VERSION 5.7 ;
  NOWIREEXTENSIONATPIN ON ;
  DIVIDERCHAR "/" ;
  BUSBITCHARS "[]" ;
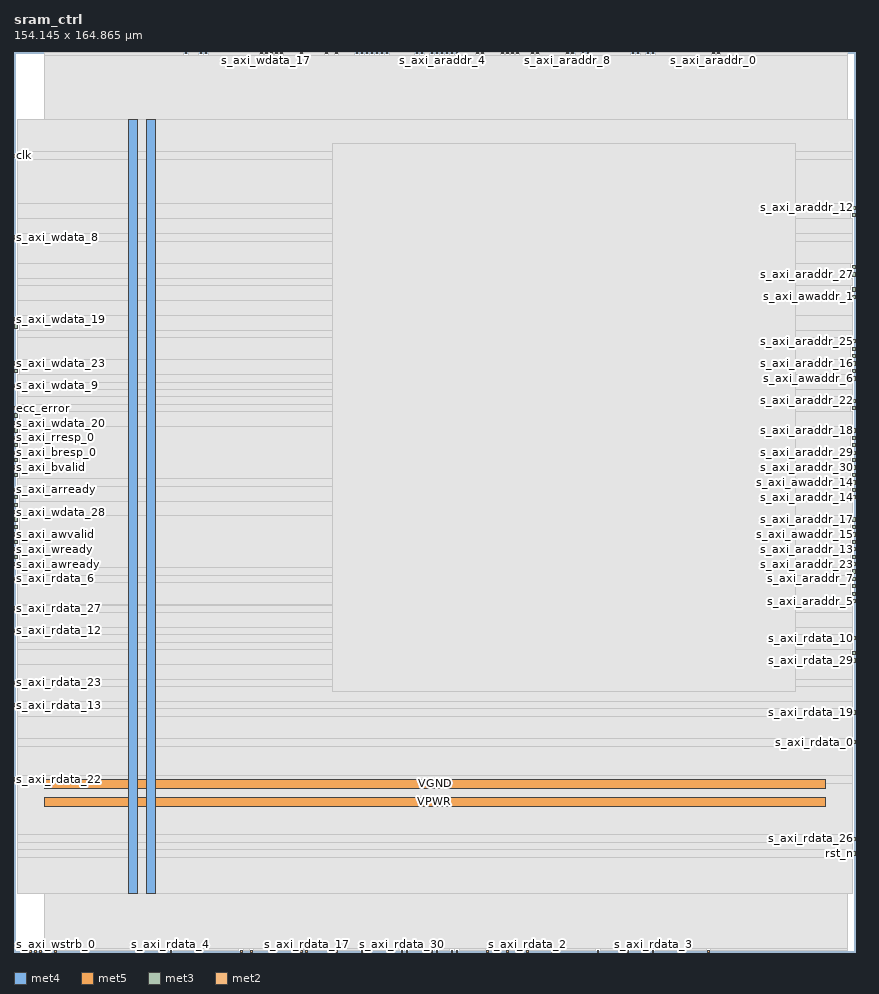
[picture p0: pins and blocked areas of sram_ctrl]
MACRO sram_ctrl
  CLASS BLOCK ;
  FOREIGN sram_ctrl ;
  ORIGIN 0.000 0.000 ;
  SIZE 154.145 BY 164.865 ;
  PIN VGND
    DIRECTION INOUT ;
    USE GROUND ;
    PORT
      LAYER met4 ;
        RECT 24.340 10.640 25.940 152.560 ;
    END
    PORT
      LAYER met5 ;
        RECT 5.520 30.030 148.580 31.630 ;
    END
  END VGND
  PIN VPWR
    DIRECTION INOUT ;
    USE POWER ;
    PORT
      LAYER met4 ;
        RECT 21.040 10.640 22.640 152.560 ;
    END
    PORT
      LAYER met5 ;
        RECT 5.520 26.730 148.580 28.330 ;
    END
  END VPWR
  PIN clk
    DIRECTION INPUT ;
    USE SIGNAL ;
    ANTENNAGATEAREA 1.286700 ;
    ANTENNADIFFAREA 0.434700 ;
    PORT
      LAYER met3 ;
        RECT 0.000 145.560 0.600 146.160 ;
    END
  END clk
  PIN ecc_error
    DIRECTION OUTPUT ;
    USE SIGNAL ;
    ANTENNAGATEAREA 0.434700 ;
    ANTENNADIFFAREA 0.775300 ;
    PORT
      LAYER met3 ;
        RECT 0.000 99.320 0.600 99.920 ;
    END
  END ecc_error
  PIN rst_n
    DIRECTION INPUT ;
    USE SIGNAL ;
    ANTENNAGATEAREA 0.647700 ;
    ANTENNADIFFAREA 0.434700 ;
    PORT
      LAYER met3 ;
        RECT 153.545 17.720 154.145 18.320 ;
    END
  END rst_n
  PIN s_axi_araddr_0
    DIRECTION INPUT ;
    USE SIGNAL ;
    ANTENNAGATEAREA 0.647700 ;
    ANTENNADIFFAREA 0.434700 ;
    PORT
      LAYER met2 ;
        RECT 127.970 164.585 128.250 164.865 ;
    END
  END s_axi_araddr_0
  PIN s_axi_araddr_1
    DIRECTION INPUT ;
    USE SIGNAL ;
    ANTENNAGATEAREA 0.647700 ;
    ANTENNADIFFAREA 0.434700 ;
    PORT
      LAYER met3 ;
        RECT 153.545 121.080 154.145 121.680 ;
    END
  END s_axi_araddr_1
  PIN s_axi_araddr_10
    DIRECTION INPUT ;
    USE SIGNAL ;
    ANTENNAGATEAREA 0.647700 ;
    ANTENNADIFFAREA 0.434700 ;
    PORT
      LAYER met2 ;
        RECT 79.210 164.585 79.490 164.865 ;
    END
  END s_axi_araddr_10
  PIN s_axi_araddr_11
    DIRECTION INPUT ;
    USE SIGNAL ;
    ANTENNAGATEAREA 0.647700 ;
    ANTENNADIFFAREA 0.434700 ;
    PORT
      LAYER met2 ;
        RECT 94.850 164.585 95.130 164.865 ;
    END
  END s_axi_araddr_11
  PIN s_axi_araddr_12
    DIRECTION INPUT ;
    USE SIGNAL ;
    ANTENNAGATEAREA 0.647700 ;
    ANTENNADIFFAREA 0.434700 ;
    PORT
      LAYER met3 ;
        RECT 153.545 136.040 154.145 136.640 ;
    END
  END s_axi_araddr_12
  PIN s_axi_araddr_13
    DIRECTION INPUT ;
    USE SIGNAL ;
    ANTENNAGATEAREA 0.647700 ;
    ANTENNADIFFAREA 0.434700 ;
    PORT
      LAYER met3 ;
        RECT 153.545 73.480 154.145 74.080 ;
    END
  END s_axi_araddr_13
  PIN s_axi_araddr_14
    DIRECTION INPUT ;
    USE SIGNAL ;
    ANTENNAGATEAREA 0.647700 ;
    ANTENNADIFFAREA 0.434700 ;
    PORT
      LAYER met3 ;
        RECT 153.545 83.000 154.145 83.600 ;
    END
  END s_axi_araddr_14
  PIN s_axi_araddr_15
    DIRECTION INPUT ;
    USE SIGNAL ;
    ANTENNAGATEAREA 0.647700 ;
    ANTENNADIFFAREA 0.434700 ;
    PORT
      LAYER met3 ;
        RECT 153.545 74.840 154.145 75.440 ;
    END
  END s_axi_araddr_15
  PIN s_axi_araddr_16
    DIRECTION INPUT ;
    USE SIGNAL ;
    ANTENNAGATEAREA 0.647700 ;
    ANTENNADIFFAREA 0.434700 ;
    PORT
      LAYER met3 ;
        RECT 153.545 107.480 154.145 108.080 ;
    END
  END s_axi_araddr_16
  PIN s_axi_araddr_17
    DIRECTION INPUT ;
    USE SIGNAL ;
    ANTENNAGATEAREA 0.647700 ;
    ANTENNADIFFAREA 0.434700 ;
    PORT
      LAYER met3 ;
        RECT 153.545 78.920 154.145 79.520 ;
    END
  END s_axi_araddr_17
  PIN s_axi_araddr_18
    DIRECTION INPUT ;
    USE SIGNAL ;
    ANTENNAGATEAREA 0.647700 ;
    ANTENNADIFFAREA 0.434700 ;
    PORT
      LAYER met3 ;
        RECT 153.545 95.240 154.145 95.840 ;
    END
  END s_axi_araddr_18
  PIN s_axi_araddr_19
    DIRECTION INPUT ;
    USE SIGNAL ;
    ANTENNAGATEAREA 0.647700 ;
    ANTENNADIFFAREA 0.434700 ;
    PORT
      LAYER met3 ;
        RECT 153.545 84.360 154.145 84.960 ;
    END
  END s_axi_araddr_19
  PIN s_axi_araddr_2
    DIRECTION INPUT ;
    USE SIGNAL ;
    ANTENNAGATEAREA 0.647700 ;
    ANTENNADIFFAREA 0.434700 ;
    PORT
      LAYER met2 ;
        RECT 80.130 0.000 80.410 0.280 ;
    END
  END s_axi_araddr_2
  PIN s_axi_araddr_20
    DIRECTION INPUT ;
    USE SIGNAL ;
    ANTENNAGATEAREA 0.647700 ;
    ANTENNADIFFAREA 0.434700 ;
    PORT
      LAYER met2 ;
        RECT 76.450 164.585 76.730 164.865 ;
    END
  END s_axi_araddr_20
  PIN s_axi_araddr_21
    DIRECTION INPUT ;
    USE SIGNAL ;
    ANTENNAGATEAREA 0.647700 ;
    ANTENNADIFFAREA 0.434700 ;
    PORT
      LAYER met2 ;
        RECT 113.250 164.585 113.530 164.865 ;
    END
  END s_axi_araddr_21
  PIN s_axi_araddr_22
    DIRECTION INPUT ;
    USE SIGNAL ;
    ANTENNAGATEAREA 0.647700 ;
    ANTENNADIFFAREA 0.434700 ;
    PORT
      LAYER met3 ;
        RECT 153.545 100.680 154.145 101.280 ;
    END
  END s_axi_araddr_22
  PIN s_axi_araddr_23
    DIRECTION INPUT ;
    USE SIGNAL ;
    ANTENNAGATEAREA 0.647700 ;
    ANTENNADIFFAREA 0.434700 ;
    PORT
      LAYER met3 ;
        RECT 153.545 70.760 154.145 71.360 ;
    END
  END s_axi_araddr_23
  PIN s_axi_araddr_24
    DIRECTION INPUT ;
    USE SIGNAL ;
    ANTENNAGATEAREA 0.647700 ;
    ANTENNADIFFAREA 0.434700 ;
    PORT
      LAYER met2 ;
        RECT 104.050 164.585 104.330 164.865 ;
    END
  END s_axi_araddr_24
  PIN s_axi_araddr_25
    DIRECTION INPUT ;
    USE SIGNAL ;
    ANTENNAGATEAREA 0.647700 ;
    ANTENNADIFFAREA 0.434700 ;
    PORT
      LAYER met3 ;
        RECT 153.545 111.560 154.145 112.160 ;
    END
  END s_axi_araddr_25
  PIN s_axi_araddr_26
    DIRECTION INPUT ;
    USE SIGNAL ;
    ANTENNAGATEAREA 0.647700 ;
    ANTENNADIFFAREA 0.434700 ;
    PORT
      LAYER met2 ;
        RECT 89.330 164.585 89.610 164.865 ;
    END
  END s_axi_araddr_26
  PIN s_axi_araddr_27
    DIRECTION INPUT ;
    USE SIGNAL ;
    ANTENNAGATEAREA 0.647700 ;
    ANTENNADIFFAREA 0.434700 ;
    PORT
      LAYER met3 ;
        RECT 153.545 123.800 154.145 124.400 ;
    END
  END s_axi_araddr_27
  PIN s_axi_araddr_28
    DIRECTION INPUT ;
    USE SIGNAL ;
    ANTENNAGATEAREA 0.647700 ;
    ANTENNADIFFAREA 0.434700 ;
    PORT
      LAYER met2 ;
        RECT 84.730 164.585 85.010 164.865 ;
    END
  END s_axi_araddr_28
  PIN s_axi_araddr_29
    DIRECTION INPUT ;
    USE SIGNAL ;
    ANTENNAGATEAREA 0.647700 ;
    ANTENNADIFFAREA 0.434700 ;
    PORT
      LAYER met3 ;
        RECT 153.545 91.160 154.145 91.760 ;
    END
  END s_axi_araddr_29
  PIN s_axi_araddr_3
    DIRECTION INPUT ;
    USE SIGNAL ;
    ANTENNAGATEAREA 0.647700 ;
    ANTENNADIFFAREA 0.434700 ;
    PORT
      LAYER met2 ;
        RECT 116.010 164.585 116.290 164.865 ;
    END
  END s_axi_araddr_3
  PIN s_axi_araddr_30
    DIRECTION INPUT ;
    USE SIGNAL ;
    ANTENNAGATEAREA 0.647700 ;
    ANTENNADIFFAREA 0.434700 ;
    PORT
      LAYER met3 ;
        RECT 153.545 88.440 154.145 89.040 ;
    END
  END s_axi_araddr_30
  PIN s_axi_araddr_31
    DIRECTION INPUT ;
    USE SIGNAL ;
    ANTENNAGATEAREA 0.647700 ;
    ANTENNADIFFAREA 0.434700 ;
    PORT
      LAYER met2 ;
        RECT 74.610 164.585 74.890 164.865 ;
    END
  END s_axi_araddr_31
  PIN s_axi_araddr_4
    DIRECTION INPUT ;
    USE SIGNAL ;
    ANTENNAGATEAREA 0.647700 ;
    ANTENNADIFFAREA 0.434700 ;
    PORT
      LAYER met2 ;
        RECT 78.290 164.585 78.570 164.865 ;
    END
  END s_axi_araddr_4
  PIN s_axi_araddr_5
    DIRECTION INPUT ;
    USE SIGNAL ;
    ANTENNAGATEAREA 0.647700 ;
    ANTENNADIFFAREA 0.434700 ;
    PORT
      LAYER met3 ;
        RECT 153.545 63.960 154.145 64.560 ;
    END
  END s_axi_araddr_5
  PIN s_axi_araddr_6
    DIRECTION INPUT ;
    USE SIGNAL ;
    ANTENNAGATEAREA 0.647700 ;
    ANTENNADIFFAREA 0.434700 ;
    PORT
      LAYER met3 ;
        RECT 153.545 106.120 154.145 106.720 ;
    END
  END s_axi_araddr_6
  PIN s_axi_araddr_7
    DIRECTION INPUT ;
    USE SIGNAL ;
    ANTENNAGATEAREA 0.647700 ;
    ANTENNADIFFAREA 0.434700 ;
    PORT
      LAYER met3 ;
        RECT 153.545 68.040 154.145 68.640 ;
    END
  END s_axi_araddr_7
  PIN s_axi_araddr_8
    DIRECTION INPUT ;
    USE SIGNAL ;
    ANTENNAGATEAREA 0.647700 ;
    ANTENNADIFFAREA 0.434700 ;
    PORT
      LAYER met2 ;
        RECT 101.290 164.585 101.570 164.865 ;
    END
  END s_axi_araddr_8
  PIN s_axi_araddr_9
    DIRECTION INPUT ;
    USE SIGNAL ;
    ANTENNAGATEAREA 0.647700 ;
    ANTENNADIFFAREA 0.434700 ;
    PORT
      LAYER met2 ;
        RECT 90.250 164.585 90.530 164.865 ;
    END
  END s_axi_araddr_9
  PIN s_axi_arready
    DIRECTION OUTPUT ;
    USE SIGNAL ;
    ANTENNAGATEAREA 0.434700 ;
    ANTENNADIFFAREA 1.137600 ;
    PORT
      LAYER met3 ;
        RECT 0.000 84.360 0.600 84.960 ;
    END
  END s_axi_arready
  PIN s_axi_arvalid
    DIRECTION INPUT ;
    USE SIGNAL ;
    ANTENNAGATEAREA 0.647700 ;
    ANTENNADIFFAREA 0.434700 ;
    PORT
      LAYER met3 ;
        RECT 0.000 83.000 0.600 83.600 ;
    END
  END s_axi_arvalid
  PIN s_axi_awaddr_0
    DIRECTION INPUT ;
    USE SIGNAL ;
    ANTENNAGATEAREA 0.647700 ;
    ANTENNADIFFAREA 0.434700 ;
    PORT
      LAYER met2 ;
        RECT 128.890 164.585 129.170 164.865 ;
    END
  END s_axi_awaddr_0
  PIN s_axi_awaddr_1
    DIRECTION INPUT ;
    USE SIGNAL ;
    ANTENNAGATEAREA 0.647700 ;
    ANTENNADIFFAREA 0.434700 ;
    PORT
      LAYER met3 ;
        RECT 153.545 119.720 154.145 120.320 ;
    END
  END s_axi_awaddr_1
  PIN s_axi_awaddr_10
    DIRECTION INPUT ;
    USE SIGNAL ;
    ANTENNAGATEAREA 0.647700 ;
    ANTENNADIFFAREA 0.434700 ;
    PORT
      LAYER met2 ;
        RECT 81.050 164.585 81.330 164.865 ;
    END
  END s_axi_awaddr_10
  PIN s_axi_awaddr_11
    DIRECTION INPUT ;
    USE SIGNAL ;
    ANTENNAGATEAREA 0.647700 ;
    ANTENNADIFFAREA 0.434700 ;
    PORT
      LAYER met2 ;
        RECT 95.770 164.585 96.050 164.865 ;
    END
  END s_axi_awaddr_11
  PIN s_axi_awaddr_12
    DIRECTION INPUT ;
    USE SIGNAL ;
    ANTENNAGATEAREA 0.647700 ;
    ANTENNADIFFAREA 0.434700 ;
    PORT
      LAYER met3 ;
        RECT 153.545 134.680 154.145 135.280 ;
    END
  END s_axi_awaddr_12
  PIN s_axi_awaddr_13
    DIRECTION INPUT ;
    USE SIGNAL ;
    ANTENNAGATEAREA 0.647700 ;
    ANTENNADIFFAREA 0.434700 ;
    PORT
      LAYER met3 ;
        RECT 153.545 72.120 154.145 72.720 ;
    END
  END s_axi_awaddr_13
  PIN s_axi_awaddr_14
    DIRECTION INPUT ;
    USE SIGNAL ;
    ANTENNAGATEAREA 0.647700 ;
    ANTENNADIFFAREA 0.434700 ;
    PORT
      LAYER met3 ;
        RECT 153.545 85.720 154.145 86.320 ;
    END
  END s_axi_awaddr_14
  PIN s_axi_awaddr_15
    DIRECTION INPUT ;
    USE SIGNAL ;
    ANTENNAGATEAREA 0.647700 ;
    ANTENNADIFFAREA 0.434700 ;
    PORT
      LAYER met3 ;
        RECT 153.545 76.200 154.145 76.800 ;
    END
  END s_axi_awaddr_15
  PIN s_axi_awaddr_16
    DIRECTION INPUT ;
    USE SIGNAL ;
    ANTENNAGATEAREA 0.647700 ;
    ANTENNADIFFAREA 0.434700 ;
    PORT
      LAYER met3 ;
        RECT 153.545 108.840 154.145 109.440 ;
    END
  END s_axi_awaddr_16
  PIN s_axi_awaddr_17
    DIRECTION INPUT ;
    USE SIGNAL ;
    ANTENNAGATEAREA 0.647700 ;
    ANTENNADIFFAREA 0.434700 ;
    PORT
      LAYER met3 ;
        RECT 153.545 77.560 154.145 78.160 ;
    END
  END s_axi_awaddr_17
  PIN s_axi_awaddr_18
    DIRECTION INPUT ;
    USE SIGNAL ;
    ANTENNAGATEAREA 0.647700 ;
    ANTENNADIFFAREA 0.434700 ;
    PORT
      LAYER met3 ;
        RECT 153.545 93.880 154.145 94.480 ;
    END
  END s_axi_awaddr_18
  PIN s_axi_awaddr_19
    DIRECTION INPUT ;
    USE SIGNAL ;
    ANTENNAGATEAREA 0.647700 ;
    ANTENNADIFFAREA 0.434700 ;
    PORT
      LAYER met3 ;
        RECT 153.545 87.080 154.145 87.680 ;
    END
  END s_axi_awaddr_19
  PIN s_axi_awaddr_2
    DIRECTION INPUT ;
    USE SIGNAL ;
    ANTENNAGATEAREA 0.647700 ;
    ANTENNADIFFAREA 0.434700 ;
    PORT
      LAYER met2 ;
        RECT 81.050 0.000 81.330 0.280 ;
    END
  END s_axi_awaddr_2
  PIN s_axi_awaddr_20
    DIRECTION INPUT ;
    USE SIGNAL ;
    ANTENNAGATEAREA 0.647700 ;
    ANTENNADIFFAREA 0.434700 ;
    PORT
      LAYER met2 ;
        RECT 77.370 164.585 77.650 164.865 ;
    END
  END s_axi_awaddr_20
  PIN s_axi_awaddr_21
    DIRECTION INPUT ;
    USE SIGNAL ;
    ANTENNAGATEAREA 0.647700 ;
    ANTENNADIFFAREA 0.434700 ;
    PORT
      LAYER met2 ;
        RECT 114.170 164.585 114.450 164.865 ;
    END
  END s_axi_awaddr_21
  PIN s_axi_awaddr_22
    DIRECTION INPUT ;
    USE SIGNAL ;
    ANTENNAGATEAREA 0.647700 ;
    ANTENNADIFFAREA 0.434700 ;
    PORT
      LAYER met3 ;
        RECT 153.545 99.320 154.145 99.920 ;
    END
  END s_axi_awaddr_22
  PIN s_axi_awaddr_23
    DIRECTION INPUT ;
    USE SIGNAL ;
    ANTENNAGATEAREA 0.647700 ;
    ANTENNADIFFAREA 0.434700 ;
    PORT
      LAYER met3 ;
        RECT 153.545 69.400 154.145 70.000 ;
    END
  END s_axi_awaddr_23
  PIN s_axi_awaddr_24
    DIRECTION INPUT ;
    USE SIGNAL ;
    ANTENNAGATEAREA 0.647700 ;
    ANTENNADIFFAREA 0.434700 ;
    PORT
      LAYER met2 ;
        RECT 104.970 164.585 105.250 164.865 ;
    END
  END s_axi_awaddr_24
  PIN s_axi_awaddr_25
    DIRECTION INPUT ;
    USE SIGNAL ;
    ANTENNAGATEAREA 0.647700 ;
    ANTENNADIFFAREA 0.434700 ;
    PORT
      LAYER met3 ;
        RECT 153.545 110.200 154.145 110.800 ;
    END
  END s_axi_awaddr_25
  PIN s_axi_awaddr_26
    DIRECTION INPUT ;
    USE SIGNAL ;
    ANTENNAGATEAREA 0.647700 ;
    ANTENNADIFFAREA 0.434700 ;
    PORT
      LAYER met2 ;
        RECT 91.170 164.585 91.450 164.865 ;
    END
  END s_axi_awaddr_26
  PIN s_axi_awaddr_27
    DIRECTION INPUT ;
    USE SIGNAL ;
    ANTENNAGATEAREA 0.647700 ;
    ANTENNADIFFAREA 0.434700 ;
    PORT
      LAYER met3 ;
        RECT 153.545 125.160 154.145 125.760 ;
    END
  END s_axi_awaddr_27
  PIN s_axi_awaddr_28
    DIRECTION INPUT ;
    USE SIGNAL ;
    ANTENNAGATEAREA 0.647700 ;
    ANTENNADIFFAREA 0.434700 ;
    PORT
      LAYER met2 ;
        RECT 85.650 164.585 85.930 164.865 ;
    END
  END s_axi_awaddr_28
  PIN s_axi_awaddr_29
    DIRECTION INPUT ;
    USE SIGNAL ;
    ANTENNAGATEAREA 0.647700 ;
    ANTENNADIFFAREA 0.434700 ;
    PORT
      LAYER met3 ;
        RECT 153.545 89.800 154.145 90.400 ;
    END
  END s_axi_awaddr_29
  PIN s_axi_awaddr_3
    DIRECTION INPUT ;
    USE SIGNAL ;
    ANTENNAGATEAREA 0.647700 ;
    ANTENNADIFFAREA 0.434700 ;
    PORT
      LAYER met2 ;
        RECT 116.930 164.585 117.210 164.865 ;
    END
  END s_axi_awaddr_3
  PIN s_axi_awaddr_30
    DIRECTION INPUT ;
    USE SIGNAL ;
    ANTENNAGATEAREA 0.647700 ;
    ANTENNADIFFAREA 0.434700 ;
    PORT
      LAYER met3 ;
        RECT 153.545 92.520 154.145 93.120 ;
    END
  END s_axi_awaddr_30
  PIN s_axi_awaddr_31
    DIRECTION INPUT ;
    USE SIGNAL ;
    ANTENNAGATEAREA 0.647700 ;
    ANTENNADIFFAREA 0.434700 ;
    PORT
      LAYER met2 ;
        RECT 73.690 164.585 73.970 164.865 ;
    END
  END s_axi_awaddr_31
  PIN s_axi_awaddr_4
    DIRECTION INPUT ;
    USE SIGNAL ;
    ANTENNAGATEAREA 0.647700 ;
    ANTENNADIFFAREA 0.434700 ;
    PORT
      LAYER met2 ;
        RECT 80.130 164.585 80.410 164.865 ;
    END
  END s_axi_awaddr_4
  PIN s_axi_awaddr_5
    DIRECTION INPUT ;
    USE SIGNAL ;
    ANTENNAGATEAREA 0.647700 ;
    ANTENNADIFFAREA 0.434700 ;
    PORT
      LAYER met3 ;
        RECT 153.545 66.680 154.145 67.280 ;
    END
  END s_axi_awaddr_5
  PIN s_axi_awaddr_6
    DIRECTION INPUT ;
    USE SIGNAL ;
    ANTENNAGATEAREA 0.647700 ;
    ANTENNADIFFAREA 0.434700 ;
    PORT
      LAYER met3 ;
        RECT 153.545 104.760 154.145 105.360 ;
    END
  END s_axi_awaddr_6
  PIN s_axi_awaddr_7
    DIRECTION INPUT ;
    USE SIGNAL ;
    ANTENNAGATEAREA 0.647700 ;
    ANTENNADIFFAREA 0.434700 ;
    PORT
      LAYER met3 ;
        RECT 153.545 65.320 154.145 65.920 ;
    END
  END s_axi_awaddr_7
  PIN s_axi_awaddr_8
    DIRECTION INPUT ;
    USE SIGNAL ;
    ANTENNAGATEAREA 0.647700 ;
    ANTENNADIFFAREA 0.434700 ;
    PORT
      LAYER met2 ;
        RECT 102.210 164.585 102.490 164.865 ;
    END
  END s_axi_awaddr_8
  PIN s_axi_awaddr_9
    DIRECTION INPUT ;
    USE SIGNAL ;
    ANTENNAGATEAREA 0.647700 ;
    ANTENNADIFFAREA 0.434700 ;
    PORT
      LAYER met2 ;
        RECT 92.090 164.585 92.370 164.865 ;
    END
  END s_axi_awaddr_9
  PIN s_axi_awready
    DIRECTION OUTPUT ;
    USE SIGNAL ;
    ANTENNAGATEAREA 0.434700 ;
    ANTENNADIFFAREA 1.137600 ;
    PORT
      LAYER met3 ;
        RECT 0.000 70.760 0.600 71.360 ;
    END
  END s_axi_awready
  PIN s_axi_awvalid
    DIRECTION INPUT ;
    USE SIGNAL ;
    ANTENNAGATEAREA 0.647700 ;
    ANTENNADIFFAREA 0.434700 ;
    PORT
      LAYER met3 ;
        RECT 0.000 76.200 0.600 76.800 ;
    END
  END s_axi_awvalid
  PIN s_axi_bready
    DIRECTION INPUT ;
    USE SIGNAL ;
    PORT
      LAYER met2 ;
        RECT 1.930 0.000 2.210 0.280 ;
    END
  END s_axi_bready
  PIN s_axi_bresp_0
    DIRECTION OUTPUT ;
    USE SIGNAL ;
    ANTENNAGATEAREA 0.434700 ;
    ANTENNADIFFAREA 0.434700 ;
    PORT
      LAYER met3 ;
        RECT 0.000 91.160 0.600 91.760 ;
    END
  END s_axi_bresp_0
  PIN s_axi_bresp_1
    DIRECTION OUTPUT ;
    USE SIGNAL ;
    ANTENNAGATEAREA 0.434700 ;
    ANTENNADIFFAREA 0.775300 ;
    PORT
      LAYER met3 ;
        RECT 0.000 92.520 0.600 93.120 ;
    END
  END s_axi_bresp_1
  PIN s_axi_bvalid
    DIRECTION OUTPUT ;
    USE SIGNAL ;
    ANTENNAGATEAREA 0.434700 ;
    ANTENNADIFFAREA 1.137600 ;
    PORT
      LAYER met3 ;
        RECT 0.000 88.440 0.600 89.040 ;
    END
  END s_axi_bvalid
  PIN s_axi_rdata_0
    DIRECTION OUTPUT ;
    USE SIGNAL ;
    ANTENNAGATEAREA 0.434700 ;
    ANTENNADIFFAREA 1.137600 ;
    PORT
      LAYER met3 ;
        RECT 153.545 38.120 154.145 38.720 ;
    END
  END s_axi_rdata_0
  PIN s_axi_rdata_1
    DIRECTION OUTPUT ;
    USE SIGNAL ;
    ANTENNAGATEAREA 0.434700 ;
    ANTENNADIFFAREA 1.137600 ;
    PORT
      LAYER met2 ;
        RECT 112.330 0.000 112.610 0.280 ;
    END
  END s_axi_rdata_1
  PIN s_axi_rdata_10
    DIRECTION OUTPUT ;
    USE SIGNAL ;
    ANTENNAGATEAREA 0.434700 ;
    ANTENNADIFFAREA 1.137600 ;
    PORT
      LAYER met3 ;
        RECT 153.545 57.160 154.145 57.760 ;
    END
  END s_axi_rdata_10
  PIN s_axi_rdata_11
    DIRECTION OUTPUT ;
    USE SIGNAL ;
    ANTENNAGATEAREA 0.434700 ;
    ANTENNADIFFAREA 1.137600 ;
    PORT
      LAYER met2 ;
        RECT 98.530 0.000 98.810 0.280 ;
    END
  END s_axi_rdata_11
  PIN s_axi_rdata_12
    DIRECTION OUTPUT ;
    USE SIGNAL ;
    ANTENNAGATEAREA 0.434700 ;
    ANTENNADIFFAREA 1.137600 ;
    PORT
      LAYER met3 ;
        RECT 0.000 58.520 0.600 59.120 ;
    END
  END s_axi_rdata_12
  PIN s_axi_rdata_13
    DIRECTION OUTPUT ;
    USE SIGNAL ;
    ANTENNAGATEAREA 0.434700 ;
    ANTENNADIFFAREA 1.137600 ;
    PORT
      LAYER met3 ;
        RECT 0.000 44.920 0.600 45.520 ;
    END
  END s_axi_rdata_13
  PIN s_axi_rdata_14
    DIRECTION OUTPUT ;
    USE SIGNAL ;
    ANTENNAGATEAREA 0.434700 ;
    ANTENNADIFFAREA 1.137600 ;
    PORT
      LAYER met2 ;
        RECT 106.810 0.000 107.090 0.280 ;
    END
  END s_axi_rdata_14
  PIN s_axi_rdata_15
    DIRECTION OUTPUT ;
    USE SIGNAL ;
    ANTENNAGATEAREA 0.434700 ;
    ANTENNADIFFAREA 1.137600 ;
    PORT
      LAYER met2 ;
        RECT 76.450 0.000 76.730 0.280 ;
    END
  END s_axi_rdata_15
  PIN s_axi_rdata_16
    DIRECTION OUTPUT ;
    USE SIGNAL ;
    ANTENNAGATEAREA 0.434700 ;
    ANTENNADIFFAREA 1.137600 ;
    PORT
      LAYER met2 ;
        RECT 127.050 0.000 127.330 0.280 ;
    END
  END s_axi_rdata_16
  PIN s_axi_rdata_17
    DIRECTION OUTPUT ;
    USE SIGNAL ;
    ANTENNAGATEAREA 0.434700 ;
    ANTENNADIFFAREA 1.137600 ;
    PORT
      LAYER met2 ;
        RECT 53.450 0.000 53.730 0.280 ;
    END
  END s_axi_rdata_17
  PIN s_axi_rdata_18
    DIRECTION OUTPUT ;
    USE SIGNAL ;
    ANTENNAGATEAREA 0.434700 ;
    ANTENNADIFFAREA 1.137600 ;
    PORT
      LAYER met2 ;
        RECT 43.330 0.000 43.610 0.280 ;
    END
  END s_axi_rdata_18
  PIN s_axi_rdata_19
    DIRECTION OUTPUT ;
    USE SIGNAL ;
    ANTENNAGATEAREA 0.434700 ;
    ANTENNADIFFAREA 1.137600 ;
    PORT
      LAYER met3 ;
        RECT 153.545 43.560 154.145 44.160 ;
    END
  END s_axi_rdata_19
  PIN s_axi_rdata_2
    DIRECTION OUTPUT ;
    USE SIGNAL ;
    ANTENNAGATEAREA 0.434700 ;
    ANTENNADIFFAREA 1.137600 ;
    PORT
      LAYER met2 ;
        RECT 93.930 0.000 94.210 0.280 ;
    END
  END s_axi_rdata_2
  PIN s_axi_rdata_20
    DIRECTION OUTPUT ;
    USE SIGNAL ;
    ANTENNAGATEAREA 0.434700 ;
    ANTENNADIFFAREA 1.137600 ;
    PORT
      LAYER met3 ;
        RECT 0.000 72.120 0.600 72.720 ;
    END
  END s_axi_rdata_20
  PIN s_axi_rdata_21
    DIRECTION OUTPUT ;
    USE SIGNAL ;
    ANTENNAGATEAREA 0.434700 ;
    ANTENNADIFFAREA 1.137600 ;
    PORT
      LAYER met2 ;
        RECT 86.570 0.000 86.850 0.280 ;
    END
  END s_axi_rdata_21
  PIN s_axi_rdata_22
    DIRECTION OUTPUT ;
    USE SIGNAL ;
    ANTENNAGATEAREA 0.434700 ;
    ANTENNADIFFAREA 1.137600 ;
    PORT
      LAYER met3 ;
        RECT 0.000 31.320 0.600 31.920 ;
    END
  END s_axi_rdata_22
  PIN s_axi_rdata_23
    DIRECTION OUTPUT ;
    USE SIGNAL ;
    ANTENNAGATEAREA 0.434700 ;
    ANTENNADIFFAREA 1.137600 ;
    PORT
      LAYER met3 ;
        RECT 0.000 49.000 0.600 49.600 ;
    END
  END s_axi_rdata_23
  PIN s_axi_rdata_24
    DIRECTION OUTPUT ;
    USE SIGNAL ;
    ANTENNAGATEAREA 0.434700 ;
    ANTENNADIFFAREA 1.137600 ;
    PORT
      LAYER met2 ;
        RECT 63.570 0.000 63.850 0.280 ;
    END
  END s_axi_rdata_24
  PIN s_axi_rdata_25
    DIRECTION OUTPUT ;
    USE SIGNAL ;
    ANTENNAGATEAREA 0.434700 ;
    ANTENNADIFFAREA 1.137600 ;
    PORT
      LAYER met2 ;
        RECT 77.370 0.000 77.650 0.280 ;
    END
  END s_axi_rdata_25
  PIN s_axi_rdata_26
    DIRECTION OUTPUT ;
    USE SIGNAL ;
    ANTENNAGATEAREA 0.434700 ;
    ANTENNADIFFAREA 1.137600 ;
    PORT
      LAYER met3 ;
        RECT 153.545 20.440 154.145 21.040 ;
    END
  END s_axi_rdata_26
  PIN s_axi_rdata_27
    DIRECTION OUTPUT ;
    USE SIGNAL ;
    ANTENNAGATEAREA 0.434700 ;
    ANTENNADIFFAREA 1.137600 ;
    PORT
      LAYER met3 ;
        RECT 0.000 62.600 0.600 63.200 ;
    END
  END s_axi_rdata_27
  PIN s_axi_rdata_28
    DIRECTION OUTPUT ;
    USE SIGNAL ;
    ANTENNAGATEAREA 0.434700 ;
    ANTENNADIFFAREA 1.137600 ;
    PORT
      LAYER met2 ;
        RECT 41.490 0.000 41.770 0.280 ;
    END
  END s_axi_rdata_28
  PIN s_axi_rdata_29
    DIRECTION OUTPUT ;
    USE SIGNAL ;
    ANTENNAGATEAREA 0.434700 ;
    ANTENNADIFFAREA 1.137600 ;
    PORT
      LAYER met3 ;
        RECT 153.545 53.080 154.145 53.680 ;
    END
  END s_axi_rdata_29
  PIN s_axi_rdata_3
    DIRECTION OUTPUT ;
    USE SIGNAL ;
    ANTENNAGATEAREA 0.434700 ;
    ANTENNADIFFAREA 1.137600 ;
    PORT
      LAYER met2 ;
        RECT 116.930 0.000 117.210 0.280 ;
    END
  END s_axi_rdata_3
  PIN s_axi_rdata_30
    DIRECTION OUTPUT ;
    USE SIGNAL ;
    ANTENNAGATEAREA 0.434700 ;
    ANTENNADIFFAREA 1.137600 ;
    PORT
      LAYER met2 ;
        RECT 70.930 0.000 71.210 0.280 ;
    END
  END s_axi_rdata_30
  PIN s_axi_rdata_31
    DIRECTION OUTPUT ;
    USE SIGNAL ;
    ANTENNAGATEAREA 0.434700 ;
    ANTENNADIFFAREA 1.137600 ;
    PORT
      LAYER met2 ;
        RECT 71.850 0.000 72.130 0.280 ;
    END
  END s_axi_rdata_31
  PIN s_axi_rdata_4
    DIRECTION OUTPUT ;
    USE SIGNAL ;
    ANTENNAGATEAREA 0.434700 ;
    ANTENNADIFFAREA 1.137600 ;
    PORT
      LAYER met2 ;
        RECT 28.610 0.000 28.890 0.280 ;
    END
  END s_axi_rdata_4
  PIN s_axi_rdata_5
    DIRECTION OUTPUT ;
    USE SIGNAL ;
    ANTENNAGATEAREA 0.434700 ;
    ANTENNADIFFAREA 1.137600 ;
    PORT
      LAYER met2 ;
        RECT 90.250 0.000 90.530 0.280 ;
    END
  END s_axi_rdata_5
  PIN s_axi_rdata_6
    DIRECTION OUTPUT ;
    USE SIGNAL ;
    ANTENNAGATEAREA 0.434700 ;
    ANTENNADIFFAREA 1.137600 ;
    PORT
      LAYER met3 ;
        RECT 0.000 68.040 0.600 68.640 ;
    END
  END s_axi_rdata_6
  PIN s_axi_rdata_7
    DIRECTION OUTPUT ;
    USE SIGNAL ;
    ANTENNAGATEAREA 0.434700 ;
    ANTENNADIFFAREA 1.137600 ;
    PORT
      LAYER met2 ;
        RECT 52.530 0.000 52.810 0.280 ;
    END
  END s_axi_rdata_7
  PIN s_axi_rdata_8
    DIRECTION OUTPUT ;
    USE SIGNAL ;
    ANTENNAGATEAREA 0.434700 ;
    ANTENNADIFFAREA 1.137600 ;
    PORT
      LAYER met3 ;
        RECT 153.545 54.440 154.145 55.040 ;
    END
  END s_axi_rdata_8
  PIN s_axi_rdata_9
    DIRECTION OUTPUT ;
    USE SIGNAL ;
    ANTENNAGATEAREA 0.434700 ;
    ANTENNADIFFAREA 1.137600 ;
    PORT
      LAYER met2 ;
        RECT 58.970 0.000 59.250 0.280 ;
    END
  END s_axi_rdata_9
  PIN s_axi_rready
    DIRECTION INPUT ;
    USE SIGNAL ;
    PORT
      LAYER met2 ;
        RECT 2.850 0.000 3.130 0.280 ;
    END
  END s_axi_rready
  PIN s_axi_rresp_0
    DIRECTION OUTPUT ;
    USE SIGNAL ;
    ANTENNAGATEAREA 0.434700 ;
    ANTENNADIFFAREA 0.775300 ;
    PORT
      LAYER met3 ;
        RECT 0.000 93.880 0.600 94.480 ;
    END
  END s_axi_rresp_0
  PIN s_axi_rresp_1
    DIRECTION OUTPUT ;
    USE SIGNAL ;
    ANTENNAGATEAREA 0.434700 ;
    ANTENNADIFFAREA 0.775300 ;
    PORT
      LAYER met3 ;
        RECT 0.000 89.800 0.600 90.400 ;
    END
  END s_axi_rresp_1
  PIN s_axi_rvalid
    DIRECTION OUTPUT ;
    USE SIGNAL ;
    PORT
      LAYER met2 ;
        RECT 3.770 0.000 4.050 0.280 ;
    END
  END s_axi_rvalid
  PIN s_axi_wdata_0
    DIRECTION INPUT ;
    USE SIGNAL ;
    ANTENNAGATEAREA 0.647700 ;
    ANTENNADIFFAREA 0.434700 ;
    PORT
      LAYER met2 ;
        RECT 52.530 164.585 52.810 164.865 ;
    END
  END s_axi_wdata_0
  PIN s_axi_wdata_1
    DIRECTION INPUT ;
    USE SIGNAL ;
    ANTENNAGATEAREA 0.647700 ;
    ANTENNADIFFAREA 0.434700 ;
    PORT
      LAYER met2 ;
        RECT 47.010 164.585 47.290 164.865 ;
    END
  END s_axi_wdata_1
  PIN s_axi_wdata_10
    DIRECTION INPUT ;
    USE SIGNAL ;
    ANTENNAGATEAREA 0.647700 ;
    ANTENNADIFFAREA 0.434700 ;
    PORT
      LAYER met2 ;
        RECT 48.850 164.585 49.130 164.865 ;
    END
  END s_axi_wdata_10
  PIN s_axi_wdata_11
    DIRECTION INPUT ;
    USE SIGNAL ;
    ANTENNAGATEAREA 0.647700 ;
    ANTENNADIFFAREA 0.434700 ;
    PORT
      LAYER met3 ;
        RECT 0.000 95.240 0.600 95.840 ;
    END
  END s_axi_wdata_11
  PIN s_axi_wdata_12
    DIRECTION INPUT ;
    USE SIGNAL ;
    ANTENNAGATEAREA 0.647700 ;
    ANTENNADIFFAREA 0.434700 ;
    PORT
      LAYER met2 ;
        RECT 47.930 164.585 48.210 164.865 ;
    END
  END s_axi_wdata_12
  PIN s_axi_wdata_13
    DIRECTION INPUT ;
    USE SIGNAL ;
    ANTENNAGATEAREA 0.647700 ;
    ANTENNADIFFAREA 0.434700 ;
    PORT
      LAYER met2 ;
        RECT 63.570 164.585 63.850 164.865 ;
    END
  END s_axi_wdata_13
  PIN s_axi_wdata_14
    DIRECTION INPUT ;
    USE SIGNAL ;
    ANTENNAGATEAREA 0.647700 ;
    ANTENNADIFFAREA 0.434700 ;
    PORT
      LAYER met3 ;
        RECT 0.000 97.960 0.600 98.560 ;
    END
  END s_axi_wdata_14
  PIN s_axi_wdata_15
    DIRECTION INPUT ;
    USE SIGNAL ;
    ANTENNAGATEAREA 0.647700 ;
    ANTENNADIFFAREA 0.434700 ;
    PORT
      LAYER met2 ;
        RECT 64.490 164.585 64.770 164.865 ;
    END
  END s_axi_wdata_15
  PIN s_axi_wdata_16
    DIRECTION INPUT ;
    USE SIGNAL ;
    ANTENNAGATEAREA 0.647700 ;
    ANTENNADIFFAREA 0.434700 ;
    PORT
      LAYER met2 ;
        RECT 35.050 164.585 35.330 164.865 ;
    END
  END s_axi_wdata_16
  PIN s_axi_wdata_17
    DIRECTION INPUT ;
    USE SIGNAL ;
    ANTENNAGATEAREA 0.647700 ;
    ANTENNADIFFAREA 0.434700 ;
    PORT
      LAYER met2 ;
        RECT 46.090 164.585 46.370 164.865 ;
    END
  END s_axi_wdata_17
  PIN s_axi_wdata_18
    DIRECTION INPUT ;
    USE SIGNAL ;
    ANTENNAGATEAREA 0.647700 ;
    ANTENNADIFFAREA 0.434700 ;
    PORT
      LAYER met2 ;
        RECT 58.970 164.585 59.250 164.865 ;
    END
  END s_axi_wdata_18
  PIN s_axi_wdata_19
    DIRECTION INPUT ;
    USE SIGNAL ;
    ANTENNAGATEAREA 0.647700 ;
    ANTENNADIFFAREA 0.434700 ;
    PORT
      LAYER met3 ;
        RECT 0.000 115.640 0.600 116.240 ;
    END
  END s_axi_wdata_19
  PIN s_axi_wdata_2
    DIRECTION INPUT ;
    USE SIGNAL ;
    ANTENNAGATEAREA 0.647700 ;
    ANTENNADIFFAREA 0.434700 ;
    PORT
      LAYER met2 ;
        RECT 62.650 164.585 62.930 164.865 ;
    END
  END s_axi_wdata_2
  PIN s_axi_wdata_20
    DIRECTION INPUT ;
    USE SIGNAL ;
    ANTENNAGATEAREA 0.647700 ;
    ANTENNADIFFAREA 0.434700 ;
    PORT
      LAYER met3 ;
        RECT 0.000 96.600 0.600 97.200 ;
    END
  END s_axi_wdata_20
  PIN s_axi_wdata_21
    DIRECTION INPUT ;
    USE SIGNAL ;
    ANTENNAGATEAREA 0.647700 ;
    ANTENNADIFFAREA 0.434700 ;
    PORT
      LAYER met2 ;
        RECT 45.170 164.585 45.450 164.865 ;
    END
  END s_axi_wdata_21
  PIN s_axi_wdata_22
    DIRECTION INPUT ;
    USE SIGNAL ;
    ANTENNAGATEAREA 0.647700 ;
    ANTENNADIFFAREA 0.434700 ;
    PORT
      LAYER met3 ;
        RECT 0.000 114.280 0.600 114.880 ;
    END
  END s_axi_wdata_22
  PIN s_axi_wdata_23
    DIRECTION INPUT ;
    USE SIGNAL ;
    ANTENNAGATEAREA 0.647700 ;
    ANTENNADIFFAREA 0.434700 ;
    PORT
      LAYER met3 ;
        RECT 0.000 107.480 0.600 108.080 ;
    END
  END s_axi_wdata_23
  PIN s_axi_wdata_24
    DIRECTION INPUT ;
    USE SIGNAL ;
    ANTENNAGATEAREA 0.647700 ;
    ANTENNADIFFAREA 0.434700 ;
    PORT
      LAYER met2 ;
        RECT 68.170 164.585 68.450 164.865 ;
    END
  END s_axi_wdata_24
  PIN s_axi_wdata_25
    DIRECTION INPUT ;
    USE SIGNAL ;
    ANTENNAGATEAREA 0.647700 ;
    ANTENNADIFFAREA 0.434700 ;
    PORT
      LAYER met2 ;
        RECT 67.250 164.585 67.530 164.865 ;
    END
  END s_axi_wdata_25
  PIN s_axi_wdata_26
    DIRECTION INPUT ;
    USE SIGNAL ;
    ANTENNAGATEAREA 0.647700 ;
    ANTENNADIFFAREA 0.434700 ;
    PORT
      LAYER met2 ;
        RECT 66.330 164.585 66.610 164.865 ;
    END
  END s_axi_wdata_26
  PIN s_axi_wdata_27
    DIRECTION INPUT ;
    USE SIGNAL ;
    ANTENNAGATEAREA 0.647700 ;
    ANTENNADIFFAREA 0.434700 ;
    PORT
      LAYER met3 ;
        RECT 0.000 106.120 0.600 106.720 ;
    END
  END s_axi_wdata_27
  PIN s_axi_wdata_28
    DIRECTION INPUT ;
    USE SIGNAL ;
    ANTENNAGATEAREA 0.647700 ;
    ANTENNADIFFAREA 0.434700 ;
    PORT
      LAYER met3 ;
        RECT 0.000 80.280 0.600 80.880 ;
    END
  END s_axi_wdata_28
  PIN s_axi_wdata_29
    DIRECTION INPUT ;
    USE SIGNAL ;
    ANTENNAGATEAREA 0.647700 ;
    ANTENNADIFFAREA 0.434700 ;
    PORT
      LAYER met3 ;
        RECT 0.000 81.640 0.600 82.240 ;
    END
  END s_axi_wdata_29
  PIN s_axi_wdata_3
    DIRECTION INPUT ;
    USE SIGNAL ;
    ANTENNAGATEAREA 0.647700 ;
    ANTENNADIFFAREA 0.434700 ;
    PORT
      LAYER met2 ;
        RECT 34.130 164.585 34.410 164.865 ;
    END
  END s_axi_wdata_3
  PIN s_axi_wdata_30
    DIRECTION INPUT ;
    USE SIGNAL ;
    ANTENNAGATEAREA 0.647700 ;
    ANTENNADIFFAREA 0.434700 ;
    PORT
      LAYER met3 ;
        RECT 0.000 77.560 0.600 78.160 ;
    END
  END s_axi_wdata_30
  PIN s_axi_wdata_31
    DIRECTION INPUT ;
    USE SIGNAL ;
    ANTENNAGATEAREA 0.647700 ;
    ANTENNADIFFAREA 0.434700 ;
    PORT
      LAYER met3 ;
        RECT 0.000 78.920 0.600 79.520 ;
    END
  END s_axi_wdata_31
  PIN s_axi_wdata_4
    DIRECTION INPUT ;
    USE SIGNAL ;
    ANTENNAGATEAREA 0.647700 ;
    ANTENNADIFFAREA 0.434700 ;
    PORT
      LAYER met2 ;
        RECT 65.410 164.585 65.690 164.865 ;
    END
  END s_axi_wdata_4
  PIN s_axi_wdata_5
    DIRECTION INPUT ;
    USE SIGNAL ;
    ANTENNAGATEAREA 0.647700 ;
    ANTENNADIFFAREA 0.434700 ;
    PORT
      LAYER met2 ;
        RECT 57.130 164.585 57.410 164.865 ;
    END
  END s_axi_wdata_5
  PIN s_axi_wdata_6
    DIRECTION INPUT ;
    USE SIGNAL ;
    ANTENNAGATEAREA 0.647700 ;
    ANTENNADIFFAREA 0.434700 ;
    PORT
      LAYER met3 ;
        RECT 0.000 87.080 0.600 87.680 ;
    END
  END s_axi_wdata_6
  PIN s_axi_wdata_7
    DIRECTION INPUT ;
    USE SIGNAL ;
    ANTENNAGATEAREA 0.647700 ;
    ANTENNADIFFAREA 0.434700 ;
    PORT
      LAYER met2 ;
        RECT 31.370 164.585 31.650 164.865 ;
    END
  END s_axi_wdata_7
  PIN s_axi_wdata_8
    DIRECTION INPUT ;
    USE SIGNAL ;
    ANTENNAGATEAREA 0.647700 ;
    ANTENNADIFFAREA 0.434700 ;
    PORT
      LAYER met3 ;
        RECT 0.000 130.600 0.600 131.200 ;
    END
  END s_axi_wdata_8
  PIN s_axi_wdata_9
    DIRECTION INPUT ;
    USE SIGNAL ;
    ANTENNAGATEAREA 0.647700 ;
    ANTENNADIFFAREA 0.434700 ;
    PORT
      LAYER met3 ;
        RECT 0.000 103.400 0.600 104.000 ;
    END
  END s_axi_wdata_9
  PIN s_axi_wready
    DIRECTION OUTPUT ;
    USE SIGNAL ;
    ANTENNAGATEAREA 0.434700 ;
    ANTENNADIFFAREA 1.137600 ;
    PORT
      LAYER met3 ;
        RECT 0.000 73.480 0.600 74.080 ;
    END
  END s_axi_wready
  PIN s_axi_wstrb_0
    DIRECTION INPUT ;
    USE SIGNAL ;
    PORT
      LAYER met2 ;
        RECT 4.690 0.000 4.970 0.280 ;
    END
  END s_axi_wstrb_0
  PIN s_axi_wstrb_1
    DIRECTION INPUT ;
    USE SIGNAL ;
    PORT
      LAYER met2 ;
        RECT 5.610 0.000 5.890 0.280 ;
    END
  END s_axi_wstrb_1
  PIN s_axi_wstrb_2
    DIRECTION INPUT ;
    USE SIGNAL ;
    PORT
      LAYER met2 ;
        RECT 6.530 0.000 6.810 0.280 ;
    END
  END s_axi_wstrb_2
  PIN s_axi_wstrb_3
    DIRECTION INPUT ;
    USE SIGNAL ;
    PORT
      LAYER met2 ;
        RECT 7.450 0.000 7.730 0.280 ;
    END
  END s_axi_wstrb_3
  PIN s_axi_wvalid
    DIRECTION INPUT ;
    USE SIGNAL ;
    ANTENNAGATEAREA 0.647700 ;
    ANTENNADIFFAREA 0.434700 ;
    PORT
      LAYER met3 ;
        RECT 0.000 74.840 0.600 75.440 ;
    END
  END s_axi_wvalid
  OBS
      LAYER nwell ;
        RECT 5.330 10.795 148.770 152.405 ;
      LAYER li1 ;
        RECT 5.520 10.795 148.580 152.405 ;
      LAYER met1 ;
        RECT 5.520 2.760 152.650 152.960 ;
      LAYER met2 ;
        RECT 5.610 164.305 31.090 164.795 ;
        RECT 31.930 164.305 33.850 164.795 ;
        RECT 34.690 164.305 34.770 164.795 ;
        RECT 35.610 164.305 44.890 164.795 ;
        RECT 45.730 164.305 45.810 164.795 ;
        RECT 46.650 164.305 46.730 164.795 ;
        RECT 47.570 164.305 47.650 164.795 ;
        RECT 48.490 164.305 48.570 164.795 ;
        RECT 49.410 164.305 52.250 164.795 ;
        RECT 53.090 164.305 56.850 164.795 ;
        RECT 57.690 164.305 58.690 164.795 ;
        RECT 59.530 164.305 62.370 164.795 ;
        RECT 63.210 164.305 63.290 164.795 ;
        RECT 64.130 164.305 64.210 164.795 ;
        RECT 65.050 164.305 65.130 164.795 ;
        RECT 65.970 164.305 66.050 164.795 ;
        RECT 66.890 164.305 66.970 164.795 ;
        RECT 67.810 164.305 67.890 164.795 ;
        RECT 68.730 164.305 73.410 164.795 ;
        RECT 74.250 164.305 74.330 164.795 ;
        RECT 75.170 164.305 76.170 164.795 ;
        RECT 77.010 164.305 77.090 164.795 ;
        RECT 77.930 164.305 78.010 164.795 ;
        RECT 78.850 164.305 78.930 164.795 ;
        RECT 79.770 164.305 79.850 164.795 ;
        RECT 80.690 164.305 80.770 164.795 ;
        RECT 81.610 164.305 84.450 164.795 ;
        RECT 85.290 164.305 85.370 164.795 ;
        RECT 86.210 164.305 89.050 164.795 ;
        RECT 89.890 164.305 89.970 164.795 ;
        RECT 90.810 164.305 90.890 164.795 ;
        RECT 91.730 164.305 91.810 164.795 ;
        RECT 92.650 164.305 94.570 164.795 ;
        RECT 95.410 164.305 95.490 164.795 ;
        RECT 96.330 164.305 101.010 164.795 ;
        RECT 101.850 164.305 101.930 164.795 ;
        RECT 102.770 164.305 103.770 164.795 ;
        RECT 104.610 164.305 104.690 164.795 ;
        RECT 105.530 164.305 112.970 164.795 ;
        RECT 113.810 164.305 113.890 164.795 ;
        RECT 114.730 164.305 115.730 164.795 ;
        RECT 116.570 164.305 116.650 164.795 ;
        RECT 117.490 164.305 127.690 164.795 ;
        RECT 128.530 164.305 128.610 164.795 ;
        RECT 129.450 164.305 152.630 164.795 ;
        RECT 5.610 0.560 152.630 164.305 ;
        RECT 6.170 0.280 6.250 0.560 ;
        RECT 7.090 0.280 7.170 0.560 ;
        RECT 8.010 0.280 28.330 0.560 ;
        RECT 29.170 0.280 41.210 0.560 ;
        RECT 42.050 0.280 43.050 0.560 ;
        RECT 43.890 0.280 52.250 0.560 ;
        RECT 53.090 0.280 53.170 0.560 ;
        RECT 54.010 0.280 58.690 0.560 ;
        RECT 59.530 0.280 63.290 0.560 ;
        RECT 64.130 0.280 70.650 0.560 ;
        RECT 71.490 0.280 71.570 0.560 ;
        RECT 72.410 0.280 76.170 0.560 ;
        RECT 77.010 0.280 77.090 0.560 ;
        RECT 77.930 0.280 79.850 0.560 ;
        RECT 80.690 0.280 80.770 0.560 ;
        RECT 81.610 0.280 86.290 0.560 ;
        RECT 87.130 0.280 89.970 0.560 ;
        RECT 90.810 0.280 93.650 0.560 ;
        RECT 94.490 0.280 98.250 0.560 ;
        RECT 99.090 0.280 106.530 0.560 ;
        RECT 107.370 0.280 112.050 0.560 ;
        RECT 112.890 0.280 116.650 0.560 ;
        RECT 117.490 0.280 126.770 0.560 ;
        RECT 127.610 0.280 152.630 0.560 ;
      LAYER met3 ;
        RECT 0.600 146.560 153.545 152.485 ;
        RECT 1.000 145.160 153.545 146.560 ;
        RECT 0.600 137.040 153.545 145.160 ;
        RECT 0.600 134.280 153.145 137.040 ;
        RECT 0.600 131.600 153.545 134.280 ;
        RECT 1.000 130.200 153.545 131.600 ;
        RECT 0.600 126.160 153.545 130.200 ;
        RECT 0.600 123.400 153.145 126.160 ;
        RECT 0.600 122.080 153.545 123.400 ;
        RECT 0.600 119.320 153.145 122.080 ;
        RECT 0.600 116.640 153.545 119.320 ;
        RECT 1.000 113.880 153.545 116.640 ;
        RECT 0.600 112.560 153.545 113.880 ;
        RECT 0.600 108.480 153.145 112.560 ;
        RECT 1.000 105.720 153.145 108.480 ;
        RECT 0.600 104.400 153.145 105.720 ;
        RECT 1.000 104.360 153.145 104.400 ;
        RECT 1.000 103.000 153.545 104.360 ;
        RECT 0.600 101.680 153.545 103.000 ;
        RECT 0.600 100.320 153.145 101.680 ;
        RECT 1.000 98.920 153.145 100.320 ;
        RECT 1.000 96.240 153.545 98.920 ;
        RECT 1.000 86.680 153.145 96.240 ;
        RECT 0.600 85.360 153.145 86.680 ;
        RECT 1.000 82.600 153.145 85.360 ;
        RECT 1.000 79.920 153.545 82.600 ;
        RECT 1.000 70.360 153.145 79.920 ;
        RECT 0.600 69.040 153.145 70.360 ;
        RECT 1.000 67.640 153.145 69.040 ;
        RECT 0.600 63.600 153.145 67.640 ;
        RECT 1.000 63.560 153.145 63.600 ;
        RECT 1.000 62.200 153.545 63.560 ;
        RECT 0.600 59.520 153.545 62.200 ;
        RECT 1.000 58.160 153.545 59.520 ;
        RECT 1.000 58.120 153.145 58.160 ;
        RECT 0.600 56.760 153.145 58.120 ;
        RECT 0.600 55.440 153.545 56.760 ;
        RECT 0.600 52.680 153.145 55.440 ;
        RECT 0.600 50.000 153.545 52.680 ;
        RECT 1.000 48.600 153.545 50.000 ;
        RECT 0.600 45.920 153.545 48.600 ;
        RECT 1.000 44.560 153.545 45.920 ;
        RECT 1.000 44.520 153.145 44.560 ;
        RECT 0.600 43.160 153.145 44.520 ;
        RECT 0.600 39.120 153.545 43.160 ;
        RECT 0.600 37.720 153.145 39.120 ;
        RECT 0.600 32.320 153.545 37.720 ;
        RECT 1.000 30.920 153.545 32.320 ;
        RECT 0.600 21.440 153.545 30.920 ;
        RECT 0.600 20.040 153.145 21.440 ;
        RECT 0.600 18.720 153.545 20.040 ;
        RECT 0.600 17.320 153.145 18.720 ;
        RECT 0.600 10.715 153.545 17.320 ;
      LAYER met4 ;
        RECT 58.255 47.775 143.225 148.065 ;
  END
END sram_ctrl
END LIBRARY

